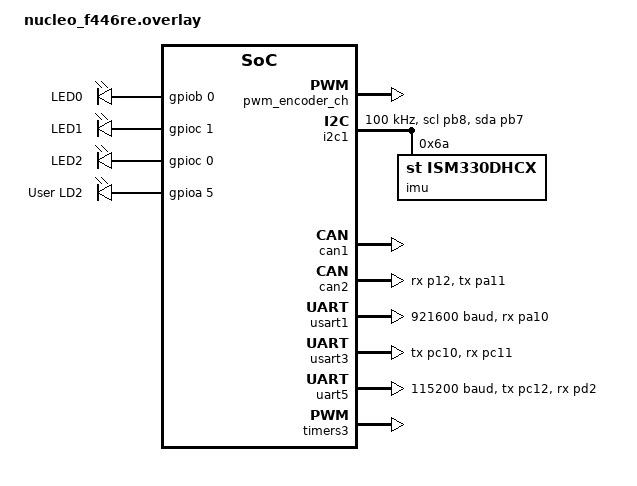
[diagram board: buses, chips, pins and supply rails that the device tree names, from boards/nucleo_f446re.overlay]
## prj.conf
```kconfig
CONFIG_MAIN_STACK_SIZE=8192

# enable GPIO subsystem
CONFIG_GPIO=y

# C++ config
CONFIG_CPP=y
CONFIG_STD_CPP17=y
CONFIG_GLIBCXX_LIBCPP=y

# CAN
CONFIG_CAN=y

# UART
CONFIG_SERIAL=y

#I2C
CONFIG_I2C=y
CONFIG_I2C_TARGET=y
# CONFIG_I2C_LOG_LEVEL_DBG=y
CONFIG_ISM330DHCX=n
CONFIG_CBPRINTF_FP_SUPPORT=y

#PWM
CONFIG_PWM=y
CONFIG_PWM_CAPTURE=y
CONFIG_PWM_LOG_LEVEL_DBG=y

#Power Management
CONFIG_PM=n
CONFIG_PM_DEVICE=y

#Asserts
CONFIG_ASSERT=y

CONFIG_HW_STACK_PROTECTION=y
CONFIG_MPU_STACK_GUARD=y

# CONFIG_THREAD_STACK_INFO=y
# CONFIG_THREAD_ANALYZER=y
# CONFIG_THREAD_ANALYZER_AUTO=y
# CONFIG_THREAD_ANALYZER_AUTO_INTERVAL=5

# These will flood your serial monitor with messages. Be aware. 
CONFIG_LOG=y
CONFIG_I2C_LOG_LEVEL_ERR=n
CONFIG_CAN_LOG_LEVEL_DBG=n 

# CONFIG_SHELL=y
CONFIG_UART_CONSOLE=y

CONFIG_CONSOLE=y
CONFIG_UART_LINE_CTRL=y

CONFIG_HEAP_MEM_POOL_SIZE=8192
```

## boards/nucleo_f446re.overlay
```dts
&i2c1 {
    pinctrl-0 = <&i2c1_scl_pb8 &i2c1_sda_pb7>;
    pinctrl-names = "default";
    status = "okay";
    clock-frequency = <100000>;

	scl-gpios = <&gpiob 8 (GPIO_ACTIVE_HIGH | GPIO_OPEN_DRAIN)>;
	sda-gpios = <&gpiob 7 (GPIO_ACTIVE_HIGH | GPIO_OPEN_DRAIN)>;

    imu: ism330@6a {
        compatible = "st,ism330dhcx";
        reg = <0x6a>;
    };
};

// ADD YOUR CAN NODES HERE
&can1{
    pinctrl-0 = <&can1_rx_pB9 &can1_tx_pB8>;
    pinctrl-names = "default";
    status = "okay";
    clock-frequency = <100000>;
    }
&can2{
    pinctrl-0 = <&can1_rx_p12 &can1_tx_pa11>;
    pinctrl-names = "default";
    status = "okay";
    clock-frequency = <100000>;
    }

&usart1 { //Controller
    pinctrl-0 = <&usart1_rx_pa10>; // tx isn't connected because this is the controller
    pinctrl-names = "default";
    status = "okay";
    current-speed = <921600>;
};

&usart3 { //Ref
    pinctrl-0 = <&usart3_tx_pc10 &usart3_rx_pc11>;
    pinctrl-names = "default";
    status = "okay";
};

&uart5 {
    pinctrl-0 = <&uart5_tx_pc12 &uart5_rx_pd2>;
    pinctrl-names = "default";
    status = "okay";
    current-speed = <115200>;
};

&timers3 { // Encoder | PWM is done thru timer node, PB_4 is timer3 channel 1
    status = "okay";
    st,prescaler = <83>;   // tune below

    pwm3: pwm {
        compatible = "st,stm32-pwm";
        status = "okay";
        pinctrl-0 = <&tim3_ch1_pb4>;
        pinctrl-names = "default";
        #pwm-cells = <3>;
    };
};

/ {
    pwm_encoder_ch: zephyr,user { //Node has to be named "zephyr,user" so it compiles
        pwms = <&pwm3 1 PWM_MSEC(20) PWM_POLARITY_NORMAL>;
        status = "okay";
    };
};

/* The sigular slash below indicates that we're just making a new node
Unlike the ones above, which were already declared for us in the
root dts file Zephyr has for us, this LED node is specific to us */
/ {
    leds {
        compatible = "gpio-leds";
        led0: led_0 {
            gpios = <&gpiob 0 GPIO_ACTIVE_HIGH>;
            label = "LED0";
        };
        led1: led_1 {
            gpios = <&gpioc 1 GPIO_ACTIVE_HIGH>;
            label = "LED1";
        };
        led2: led_2 {
            gpios = <&gpioc 0 GPIO_ACTIVE_HIGH>;
            label = "LED2";
        };

        LD2: LD_2 {
            gpios = <&gpioa 5 GPIO_ACTIVE_HIGH>;
            label = "User LD2";
        };
    };

    aliases {
        //Left hand side lives in a diff namespace than right hand side
        //So this doesn't break everything I swear
        led0 = &led0;
        led1 = &led1;
        led2 = &led2;
    };
};

  &gpiob {
       status = "okay";
   };

   &gpioc {
       status = "okay";
   };
```

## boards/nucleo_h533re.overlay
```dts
&fdcan1 {
    status = "okay";
    pinctrl-0 = <&fdcan1_rx_pb8 &fdcan1_tx_pb7>;
    pinctrl-names = "default";
    bitrate = <1000000>;
};

&fdcan2 {
    status = "okay";
    pinctrl-0 = <&fdcan2_rx_pb5 &fdcan2_tx_pb6>;
    pinctrl-names = "default";
    bitrate = <1000000>;
};

&i2c1 {
    pinctrl-0 = <&i2c1_scl_pb8 &i2c1_sda_pb7>;
    pinctrl-names = "default";
    status = "okay";
    clock-frequency = <100000>;

	scl-gpios = <&gpiob 8 (GPIO_ACTIVE_HIGH | GPIO_OPEN_DRAIN)>;
	sda-gpios = <&gpiob 7 (GPIO_ACTIVE_HIGH | GPIO_OPEN_DRAIN)>;

    imu: ism330@6a {
        compatible = "st,ism330dhcx";
        reg = <0x6a>;
    };
};

&usart1 { //Controller
    pinctrl-0 = <&usart1_rx_pa10>; // tx isn't connected because this is the controller
    pinctrl-names = "default";
    status = "okay";
    current-speed = <921600>;
};

&usart3 { //Ref
    pinctrl-0 = <&usart3_tx_pc10 &usart3_rx_pc11>;
    pinctrl-names = "default";
    status = "okay";
};

&uart5 {
    status="okay"
}

&timers3 { // Encoder | PWM is done thru timer node, PB_4 is timer3 channel 1
    status = "okay";
    st,prescaler = <83>;   // tune below

    pwm3: pwm {
        compatible = "st,stm32-pwm";
        status = "okay";
        pinctrl-0 = <&tim3_ch1_pb4>;
        pinctrl-names = "default";
        #pwm-cells = <3>;
    };
};

/ {
    pwm_encoder_ch: zephyr,user { //Node has to be named "zephyr,user" so it compiles
        pwms = <&pwm3 1 PWM_MSEC(20) PWM_POLARITY_NORMAL>;
        status = "okay";
    };
};

/* The sigular slash below indicates that we're just making a new node
Unlike the ones above, which were already declared for us in the
root dts file Zephyr has for us, this LED node is specific to us */
/ {
    leds {
        compatible = "gpio-leds";
        led0: led_0 {
            gpios = <&gpiob 0 GPIO_ACTIVE_HIGH>;
            label = "LED0";
        };
        led1: led_1 {
            gpios = <&gpioc 1 GPIO_ACTIVE_HIGH>;
            label = "LED1";
        };
        led2: led_2 {
            gpios = <&gpioc 0 GPIO_ACTIVE_HIGH>;
            label = "LED2";
        };

        LD2: LD_2 {
            gpios = <&gpioa 5 GPIO_ACTIVE_HIGH>;
            label = "User LD2";
        };
    };

    aliases {
        //Left hand side lives in a diff namespace than right hand side
        //So this doesn't break everything I swear
        led0 = &led0;
        led1 = &led1;
        led2 = &led2;
    };
};

  &gpiob {
       status = "okay";
   };

   &gpioc {
       status = "okay";
   };
```

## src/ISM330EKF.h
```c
/**
* @file ISM330EKF.h
* @brief SPI driver for the ISM330DHCX 6-DoF accelerometer and gyroscope.
*
* This class provides a lightweight interface for communicating with the
* ST ISM330DHCX sensor over SPI using Mbed OS. It supports basic device
* initialization and simple readout of accelerometer and gyroscope data.
*
* The sensor must be externally configured for range, filtering and output
* data rate before sampling values.
*/
#pragma once

#ifndef ISM330EKF_H_
#define ISM330EKF_H_
#include <zephyr/device.h>
#include <zephyr/devicetree.h>
#include <zephyr/drivers/i2c.h>
#include "util/peripherals/imu/IMU.h"
#include <cstdint>

/**
 * @class ISM330
 * @brief Interface class for ISM330DHCX IMU using SPI.
 */
class ISM330 : public IMU {
public:
    // Structs
    typedef struct {
        float x;
        float y;
        float z;
    } ISM330_VECTOR_TypeDef;

    typedef struct {
        int16_t ax;
        int16_t ay;
        int16_t az;
        int16_t gx;
        int16_t gy;
        int16_t gz;
    } ISM330_RAW_DATA_TypeDef;

    typedef struct {
        float ax;
        float ay;
        float az;
        float gx;
        float gy;
        float gz;
    } ISM330_DATA_TypeDef;

    ISM330(const struct i2c_dt_spec &i2c) noexcept;

    /**
    * @brief Initialize communication with the device.
    *
    * Performs basic SPI setup and verifies device presence using the WHO_AM_I
    * register.
    *
    * @return true if the device identifier matches the expected chip ID.
    * @return false if device detection fails.
    */
    bool begin(float prop_gain=0.1f, float int_gain=0.0f) noexcept;

    // /** Deprecated?
    // * @brief Read the WHO_AM_I register value.
    // *
    // * This value should match the documented device ID. Mainly useful for
    // * diagnostics or verifying hardware connectivity.
    // *
    // * @return 8-bit device identifier.
    // */
    // uint8_t whoAmI() noexcept;
    
    /**
    * @brief Issue a software reset to the device.
    *
    * Triggers a soft reset and blocks briefly to allow the device to restart.
    */
    void reset() noexcept;
    
    void calibrate() noexcept; 
    
    IMU::EulerAngles getImuAngles() override;
    
    IMU::EulerAngles read() override { return getImuAngles(); }

   //Full read functions
    //Reads Accel and Gyro sequentially, reduces I2C transactions
    ISM330_RAW_DATA_TypeDef readAGraw() noexcept; //used during calibration

    ISM330_DATA_TypeDef readAG() noexcept;

    // Temperature Reading
    float readTemperature() noexcept; // Returns temp in C-25, so at 25C it should read 0
    // If you're wondering why, it's just how the IMU is calibrated

    float accelTempScale(float temp); // Returns the scaling of the accelerometer with respect to Temperature; At 25C = 0;

    float accelTempOffset(float temp); // Returns the offset of the accelerometer with respect to Temperature; At 25C = 0; (Just adding a constant)

    float gyroTempScale(float temp); // Returns the scaling of the gyro with respect to Temperature; At 25C = 0;

    float gyroTempOffset(float temp); // Returns the offset of the gyro with respect to Temperature; At 25C = 0; (Just adding a constant)

    // Update Structs
    void getAGVectors(ISM330_VECTOR_TypeDef& accel, ISM330_VECTOR_TypeDef& gyro);

    // IMU Sensor Fusion
    void computeAnglesMah(IMU::EulerAngles& angles); // Mahony Compute Euler Angles

    void computeAnglesEKF(IMU::EulerAngles& angles);
    
    // void computeAnglesMadgwick(IMU::EulerAngles& angles);
    
    // Mahony Sensor Fusion
    //Adafruit_Mahony(float prop_gain, float int_gain);
    void mahonyStart(float prop_gain, float int_gain);

    void initQuaternionFromAccel();
    
    void mahonyUpdate(float mx, float my, float mz, float dt);
    
    void mahonyUpdateIMU(float dt);

    //EKF Seneor Fusion

    void ekfStart();
    
    void ekfPredict(float gx, float gy, float gz, float dt);

    void ekfUpdate(float ax, float ay, float az);

    void ekfReset(float dtheta[3], float dbias[3]);

    void quatMul(float out[4], const float a[4], const float b[4]);

    void quatNormalize(float q[4]);

    void QuatFromRotVec(float q[4], const float rv[3]);

    void rotMatFromQuat(float R[3][3], const float q[4]);
    
    // Madgwick Sensor Fusion

    // void madgwickStart(float gain);
    
    // void madgwickUpdate(float mx, float my, float mz, float dt);
    
    // void madgwickUpdateIMU(float dt);

    // Reading individual sensor values
    ISM330_VECTOR_TypeDef readAccel() noexcept;

    ISM330_VECTOR_TypeDef readGyro() noexcept;
    
private:
    struct i2c_dt_spec i2c_;
    uint8_t _address;
    uint8_t whoAmIReading;

    // Raw offsets for accel and gyro
    float axBias;
    float ayBias;
    float azBias;
    float wxBias;
    float wyBias;
    float wzBias;
    
    //Raw I2C readings to actual measurements
    uint8_t agReadings[14]; //Temperature, Accel and Gyro Readings buffer
    uint8_t xReadings[6]; //Accel Readings buffer
    uint8_t gReadings[6]; //Gyro Readings buffer
    float temperature; //Temperature in C-25, so at 25C it should read 0

    void writeReg(const uint8_t *cmd, size_t len) noexcept; //cmd points to some array starting with the register, and then the value(s)
    void readReg(uint8_t reg, uint8_t *out, size_t len) noexcept; 

    ISM330_VECTOR_TypeDef readingToAccel(const uint8_t *readings, float temp);
    
    ISM330_VECTOR_TypeDef readingToGyro(const uint8_t *readings, float temp);
        
    float invSqrt(float x); //Inverse square root, used for normalizing vectors
    
    float beta; // algorithm gain
    float q0;
    float q1;
    float q2;
    float q3; // quaternion of sensor frame relative to auxiliary frame
    float invSampleFreq;
    float grav[3]; // gravity vector 

    //Mahony Quaternions
    float mahq0;
    float mahq1;
    float mahq2;
    float mahq3;

    float twoKp; // 2 * proportional gain (Kp)
    float twoKi; // 2 * integral gain (Ki)
    float integralFBx, integralFBy, integralFBz; // integral error terms scaled by Ki

    //EKF 
    float ekfq0;
    float ekfq1;
    float ekfq2;
    float ekfq3;
    float gyro_bias[3];  // Estimated gyro bias (rad/s)
    float P[6][6];       // Error covariance matrix (6x6)

    //EKF tuning parameters
    float sigma_gyro;    // Gyro noise (rad/s/sqrt(Hz))
    float sigma_bias;    // Bias random walk (rad/s/sqrt(s))
    float sigma_accel;   // Accelerometer noise (m/s^2)

    bool anglesComputed = false; // Flag for whether or not angles have been computed
};

#endif // ISM330EKF_H_
```

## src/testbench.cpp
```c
#include <util/peripherals/imu/ISM330.h>
#include "zephyr/drivers/i2c.h"
#include <cmath>
#include <cstdint>
#include <util/algorithms/general_functions.h>

#define ISM330_NODE DT_NODELABEL(imu)

float EKF_yaw;
float EKF_pitch;
float EKF_roll;

float MAH_yaw;
float MAH_pitch;
float MAH_roll;

const int64_t period_ms = 10; //100 Hz

static const struct i2c_dt_spec ism_i2c = I2C_DT_SPEC_GET(ISM330_NODE);
ISM330 imu(ism_i2c);

static IMU::EulerAngles mahAngles;
static IMU::EulerAngles ekfAngles;

void periodic() {
    // Mahony
    imu.mahonyUpdateIMU(period_ms / 1000.0f);
    imu.computeAnglesMah(mahAngles);
    MAH_roll  = mahAngles.roll;
    MAH_pitch = mahAngles.pitch;
    MAH_yaw   = mahAngles.yaw;

    // EKF
    imu.computeAnglesEKF(ekfAngles);
    EKF_roll = ekfAngles.roll;
    EKF_pitch = ekfAngles.pitch;
    EKF_yaw = ekfAngles.yaw;

    printf("Mahony: Roll: %.2f, Pitch: %.2f, Yaw: %.2f\n", MAH_roll, MAH_pitch, MAH_yaw);
    printf("EKF: Roll: %.2f, Pitch: %.2f, Yaw: %.2f\n", EKF_roll, EKF_pitch, EKF_yaw);
}

int main(void){
    if (!i2c_is_ready_dt(&ism_i2c)) {
        printf("I2C device not ready.");
        return -1;
    }

    i2c_recover_bus(ism_i2c.bus);

    if (!imu.begin(0.1f, 0.0f)) {
        printf("ISM330 initialization failed.");
        return -1;
    }
    printf("ISM330 initialized.");

    imu.ekfStart();

    int64_t next_wake = k_uptime_get(); 

    uint32_t i = 0;

    while (true) {
        periodic();

        i++;

        next_wake += period_ms;
        int64_t sleep_ms = next_wake - k_uptime_get();
        if (sleep_ms > 0) {
            k_sleep(K_MSEC(sleep_ms));
        } else {
            next_wake = k_uptime_get();
        }
    }

    return 0;
}
```

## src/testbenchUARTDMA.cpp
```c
/* Jank but working DMA UART check, make sure prj.conf has 
CONFIG_DMA=y
CONFIG_UART_ASYNC_API=y
*/

#include <zephyr/kernel.h>
#include <zephyr/device.h>
#include <zephyr/drivers/uart.h>
#include <zephyr/sys/printk.h>
#include <zephyr/sys/ring_buffer.h>
#include <string.h>

#define REF_NODE   DT_NODELABEL(usart3)
#define CTRL_NODE  DT_NODELABEL(usart1)

static const struct device *const uart_ref  = DEVICE_DT_GET(REF_NODE);
static const struct device *const uart_ctrl = DEVICE_DT_GET(CTRL_NODE);

/* Double-buffered DMA RX buffers for USART1 */
#define RX_BUF_LEN 64
static uint8_t rx_buf_a[RX_BUF_LEN];
static uint8_t rx_buf_b[RX_BUF_LEN];

/* Decouples the fast DMA callback from the slow printk() consumer */
RING_BUF_DECLARE(rx_rb, 512);

int ret;

static void ctrl_uart_cb(const struct device *dev,
                         struct uart_event *evt,
                         void *user_data)
{
    ARG_UNUSED(user_data);

    switch (evt->type) {

    case UART_RX_RDY:
        printk(">>> UART_RX_RDY: offset=%d len=%d\n",
               evt->data.rx.offset,
               evt->data.rx.len);

        /* Keep your existing ring-buffer code */
        ring_buf_put(&rx_rb,
                     &evt->data.rx.buf[evt->data.rx.offset],
                     evt->data.rx.len);
        break;

    case UART_RX_BUF_REQUEST: {
        printk(">>> UART_RX_BUF_REQUEST\n");

        static bool use_a;
        uint8_t *next = use_a ? rx_buf_a : rx_buf_b;

        use_a = !use_a;

        int ret = uart_rx_buf_rsp(dev, next, RX_BUF_LEN);

        printk(">>> uart_rx_buf_rsp() = %d, buffer=%s\n",
               ret,
               (next == rx_buf_a) ? "A" : "B");

        break;
    }

    case UART_RX_BUF_RELEASED:
        printk(">>> UART_RX_BUF_RELEASED: buf=%s\n",
               (evt->data.rx_buf.buf == rx_buf_a) ? "A" : "B");
        break;

    case UART_RX_DISABLED:
        printk(">>> UART_RX_DISABLED\n");
        break;

    default:
        printk(">>> UART event: %d\n", evt->type);
        break;
    }
}

int main(void)
{
	if (!device_is_ready(uart_ref)) {
		printk("USART3 (ref) not ready\n");
		return -1;
	}
	if (!device_is_ready(uart_ctrl)) {
		printk("USART1 (ctrl) not ready\n");
		return -1;
	}

    printk("USART1 name: %s\n", uart_ctrl->name);
    printk("USART1 ready: %d\n", device_is_ready(uart_ctrl));
    printk("USART1 api: %p\n", (void *)uart_ctrl->api);

    ret = uart_callback_set(uart_ctrl, ctrl_uart_cb, NULL);
    printk("uart_callback_set: %d\n", ret);

    ret = uart_rx_enable(uart_ctrl, rx_buf_a, RX_BUF_LEN,
                     50 * USEC_PER_MSEC);
    printk("uart_rx_enable: %d\n", ret);

	const char *msg = "Hello from USART3!\r\n";
	int count = 0;
	uint8_t drain[64];

	while (1) {
		printk("TX -> [%d] %s", count, msg);

		for (const char *p = msg; *p != '\0'; p++) {
			uart_poll_out(uart_ref, *p);
		}
		count++;

		/* Safe to printk here -- we're in thread context, not the DMA callback */
		uint32_t n;

		while ((n = ring_buf_get(&rx_rb, drain, sizeof(drain))) > 0) {
			for (uint32_t i = 0; i < n; i++) {
				printk("RX <- 0x%02x ('%c')\n", drain[i],
				       (drain[i] >= 32 && drain[i] < 127) ? drain[i] : '.');
			}
		}

		k_sleep(K_MSEC(1000));
	}

	return 0;
}
```

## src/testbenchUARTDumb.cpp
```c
// Remember to Edit prj.conf and make sure CONFIG_UART_INTERRUPT_DRIVEN=y
```
